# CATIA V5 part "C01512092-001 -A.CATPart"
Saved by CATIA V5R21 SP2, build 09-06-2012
Part number: C01512092-001
Revision: ---
Description: PROPRIETARY NOTICE (do not delete / modify)  ***************************************************************************************************  LA SOCIETE EN COMMANDITE  AIRBUS CANADA  ("AIRBUS CANADA")  PAR  L'INTERMEDIAIRE  DE  SES  DIVISIONS  ET/OU  FILIALES  CORPORATIVES,  FOURNIT  LES PRESENTES  INFORMATIONS  AU  GOUVERNEMENT  A  TITRE CONFIDENTIEL. CES  INFORMATIONS ONT UNE TENEUR CONFIDENTIELLE,  AVEC DROITS DE PROPRIETE,  ET NOUS LES CONSIDERONS  EXCLUS  DE   L'APPLICATION  DE  LA LOI SUR L'ACCES A L'INFORMATION  (CANADA),  LES  LOIS  SUR  L'ACCES  A  L'INFORMATION  EUROPEENNES,  LE FREEDOM OF INFORMATION ACT (ETATS-UNIS) ET D'AUTRES LOIS SEMBLABLES. ELLES  PEUVENT  AUSSI  CONSTITUER DES SECRETS INDUSTRIELS DE NOTRE SOCIETE OU DE TIERCES PARTIES. LA DIVULGATION  PUBLIQUE  DE CES  INFORMATIONS NUIRAIT A AIRBUS CANADA OU A DES TIERCES PARTIES.  CES INFORMATIONS PEUVENT EGALEMENT CONTENIR  DES DONNEES QUI SONT CONTROLEE PAR DES LOIS DE CONTROLE DES EXPORTATIONS DU CANADA, L’EUROPE OU LES  ETATS-  UNIS. TOUTE EXPORTATION OU REEXPORTATION DE DONNEES CONTROLEES SANS AUTORISATION EST STRICTEMENT INTERDITE.  TOUTE INTENTION DE LES DIVULGUER EN TOUT OU EN PARTIE DEVRA ETRE SIGNIFIEE A L'AVANCE ET PAR ECRIT AU VICE-  PRESIDENT, SERVICES JURIDIQUES ET CONFORMITE ET SECRETAIRE CORPORATIF D'AIRBUS CANADA.    AIRBUS CANADA LIMITED PARTNERSHIP  ("AIRBUS CANADA"),  BY ITS AFFILIATES AND/OR SUBSIDIARIES, PROVIDES THIS  INFORMATION TO THE GOVERNMENT IN CONFIDENCE. THIS IS PROPRIETARY CONFIDENTIAL INFORMATION WHICH WE CONSIDER  EXCLUDED  FROM  THE  APPLICATION OF THE ACCESS TO INFORMATION ACT (CANADA),  THE FREEDOM OF INFORMATION ACT  (U.S.A.),  THE ACCESS TO INFORMATION LAWS IN EUROPE, AND OTHER SIMILAR LEGISLATION. AND MAY ALSO CONSTITUTE  TRADE SECRETS OF OUR  COMPANY OR THIRD PARTIES.  PUBLIC  RELEASE  OF  THIS INFORMATION  WOULD BE HARMFUL TO  AIRBUS CANADA OR THIRD PARTIES.  THIS  INFORMATION  MAY  ALSO  CONTAIN DATA THAT IS CONTROLLED BY CANADIAN,  EUROPEAN, OR U.S.A. EXPORT CONTROL LAWS. ANY UNAUTHORIZED EXPORT OR RE-EXPORT OF ANY EXPORT CONTROLLED DATA  IS STRICTLY PROHIBITED  ANY INTENTION TO DISCLOSE SUCH INFORMATION,  OR  PART THEREOF,  MUST BE NOTIFIED IN  ADVANCE AND IN WRITING TO THE VICE PRESIDENT, LEGAL AND COMPLIANCE AND CORPORATE SECRETARY OF AIRBUS CANADA.        LES RENSEIGNEMENTS,  LES DONNEES  ET  DESSINS  TECHNIQUES  DIVULGUES  DANS  LES PRESENTES SONT LA PROPRIETE  EXCLUSIVE DE LA SOCIETE EN COMMANDITE AIRBUS CANADA ("AIRBUS CANADA") OU COMPORTENT DES DROITS DE PROPRIETE  APPARTENANT  A  AUTRUI ET NE PEUVENT ETRE DIVULGUES  A  QUICONQUE  NI  UTILISES PAR QUI QUE CE SOIT SANS LE  CONSENTEMENT  ECRIT  D’AIRBUS  CANADA.  LE DETENTEUR DES  PRESENTES  S'ENGAGE, DANS TOUTES CIRCONSTANCES, A  GARDER CONFIDENTIELS LES DONNEES ET DESSINS TECHNIQUES QU'ELLES CONTIENNENT.   CE QUI PRECEDE NE S'APPLIQUE  PAS  AUX PERSONNES  QUI  ONT DES DROITS DE PROPRIETE SUR CES RENSEIGNEMENTS,  DONNEES TECHNIQUES ET DESSINS  DANS LA MESURE OU CES DROITS EXISTENT.    THE INFORMATION,  TECHNICAL DATA  AND  DESIGNS DISCLOSED HEREIN ARE THE EXCLUSIVE PROPERTY OF AIRBUS CANADA  LIMITED PARTNERSHIP  ("AIRBUS CANADA")  OR  CONTAIN PROPRIETARY RIGHTS OF OTHERS  AND ARE NOT TO BE USED OR  DISCLOSED  TO  OTHERS WITHOUT THE WRITTEN CONSENT OF AIRBUS CANADA.  THE RECIPIENT OF THIS DOCUMENT, BY ITS  RETENTION  AND  USE  AGREES TO  HOLD  IN  CONFIDENCE  THE  TECHNICAL DATA AND DESIGNS CONTAINED HEREIN. THE  FOREGOING SHALL NOT APPLY TO PERSONS HAVING PROPRIETARY RIGHTS TO SUCH INFORMATION,  TECHNICAL DATA OR SUCH  DESIGNS TO THE EXTENT THAT SUCH RIGHTS EXIST.    Copyright 2020 Airbus Canada Limited Partnership. All Rights Reserved.  ***********************************
Property "Title": "LEVER, LIFT, FWD PASS DR"
Property "Dataset Type": "DETAIL"
Property "Supplier Name And CAGE Code": "AIRBUS CANADA LIMITED PARTNERSHIP L0J48"
Property "Major Supplier Code": "LP"
Property "3D Only": "N/A"
Property "Material Form": "BAR - FLAT"
Property "Finish Code": "S010"
Property "PCCN": "2"
Property "Organization": "DESIGN"
Property "Design Authority Program": "BD-500"
Property "Color Coded": "N/A"
Property "Thickness": 1.5
Property "Inside Diameter": 0
Property "Outside Diameter": 0
Property "Length": 0
Property "Width": 3.75
Property "Wall": 0
Property "Wire Gauge": "-"
Property "Alloy": "PH13-8MO"
Property "Final Condition": "H1000"
Property "Density": "N/A"
Property "Form": "N/A"
Property "Grade/Composition": "N/A"
Property "Material Class": "N/A"
Property "Mesh Cell Size": "N/A"
Property "Standard Spec Die": "N/A"
Property "Type": "N/A"
Property "Style": "N/A"
Property "MFG Process": "MACHINED"
Property "Material Specification Production": "AMS5629"
Property "Material Description Production": "CRES"
Property "Dimensions": "DIMENSIONS ARE IN INCHES"
Property "Roughness": "ALL MACHINED SURFACES 125 Ra MAX"
Property "Eng. Tolerances": "LINEAR .XX= +/-.03; .XXX= +/-.010; ANGULAR= +/-0.5 DEG"
Property "Tool Design Tolerances": "LINEAR .X= +/-.06; .XX= +/-.015; .XXX= +/-.005; .XXXX= +/-.001; ANGULAR= +/-0.5 DEG"
Property "Project": "BA"
Publications: "PartBody", "REFERENCE ORIENTATION", "REFERENCE PLANE", "REFERENCE AXIS", "Extract.1_Datum_A", "Extract.1_Datum_B", "Extract.1_Datum_C", "Extract.1_Datum_D"
Material "CRES-PH-13-8-MO-BAR": density 7750.37 kg/m3
Bounding box of the stored display mesh (mm): x -178.816 to 0, y -14.604 to 14.604, z -21.456 to 69.533
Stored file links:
  C:\Users\CQQZ006\Desktop\A220钢钛件\舱门\C01512092-001\C01512092-001 -A.CATPart
  I:\Standard\Materials\Textures\steel100.jpeg

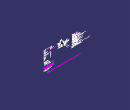
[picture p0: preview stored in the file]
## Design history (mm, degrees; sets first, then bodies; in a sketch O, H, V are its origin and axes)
Part_3D_Annotations1 "CATTPSSet"
AxisSystem1: origin (0, 0, 0), X (1, 0, 0), Y (0, 1, 0), Z (0, 0, 1)
Set1 "Pilot_Holes"
  Set2 "1/4"
    Set3 "Copied From C01512050-001"
      Line1 "Fix Orientation 1": stored without definition
      Point1 "Fix Point 1": stored without definition
      Line2 "Fix Orientation 2": stored without definition
      Point2 "Fix Point 2": stored without definition
Set4 "References"
  Line3 "REFERENCE ORIENTATION": type PtDir, RefPoint Point3, Direction yz-plane, Start -25.4, End 6.35
  Plane1 "REFERENCE PLANE": type Offset, RefPlane face of Shaft1 from Sketch1.L10, Offset 0, reversed
  Line4 "REFERENCE AXIS": type PtPt, FirstPoint Point4, SecondPoint Point5
Set5 "Geometrical Set for 3D Annotations"
  Set6 "No Show Geometry"
    Extract1 "Extract.1_Datum_A": ExtractElem face of Shaft1 from Sketch1.L11
    Extract2 "Extract.1_Datum_B": ExtractElem face of Shaft1 from Sketch1.L4
    Extract3 "Extract.1_Datum_C": ExtractElem face of Pocket1 from Sketch2.A3
    Extract4 "Extract.1_Datum_D": ExtractElem end face of Pocket2
  Set7 "Surfaces for 3D Annotations"
    Plane2: type Offset, RefPlane face of Shaft1 from Sketch1.L7, Offset 2.54, reversed
    Split1: ToCut {extract ExtractElem face of Shaft1 from Sketch1.L8}, Cutting Plane2
Set8 "Construction_Geometry"
  Point3: type Center, Curve edge [face of Chamfer2 | face of Shaft1 from Sketch1.L1]
  Point4: type Center, Curve edge [end face of Pocket2 | face of Shaft1 from Sketch1.L12]
  Point5: type Center, Curve edge [face of Shaft1 from Sketch1.L9 | face of Shaft1 from Sketch1.L14]
Body1 (main body)
  Sketch1 on zx-plane, origin (0, 0, 0), H (-1, 0, 0), V (0, 0, 1)
    line L1 (0, 9.525) -> (0, 76.2)
    line L2 (0, 76.2) -> (15.24, 76.2)
    line L3 (15.24, 76.2) -> (15.24, 19.064)
    arc A1 centre (20.828, 19.064) radius 5.588 from (15.24, 19.064) to (20.828, 13.476) ccw
    line L4 (20.828, 13.476) -> (41.91, 13.476)
    point P6 (41.91, 13.476)
    arc A2 centre (47.7279, 24.765) radius 12.7 from (41.91, 13.476) to (47.7279, 12.065) ccw
    line L5 (47.7279, 12.065) -> (105.4477, 12.065)
    arc A3 centre (105.4477, 24.765) radius 12.7 from (105.4477, 12.065) to (109.347, 12.6784) ccw
    line L6 (161.163, 9.5072) -> (167.386, 9.5072)
    line L7 (167.386, 9.5072) -> (167.386, 6.604)
    line L8 (167.64, 6.35) -> (178.816, 6.35)
    line L9 (178.816, 6.35) -> (178.816, 3.175)
    line L10 (160.909, 9.7612) -> (160.909, 12.6784)
    point P13 (160.909, 12.6784)
    line L11 (160.909, 12.6784) -> (109.347, 12.6784)
    point P14 (109.347, 12.6784)
    arc A4 centre (161.163, 9.7612) radius 0.254 from (160.909, 9.7612) to (161.163, 9.5072) ccw
    line L12 (0, 9.525) -> (154.559, 9.525)
    point P18 (154.559, 9.525)
    line L13 (154.559, 9.525) -> (158.2252, 3.175)
    line L14 (158.2252, 3.175) -> (178.816, 3.175)
    construction line L15 (116.4249, -12.6784) -> (142.4659, -12.6784)
    construction line L16 (161.544, -9.5072) -> (167.3073, -9.5072)
    construction line L17 (23.5752, -13.476) -> (37.3676, -13.476)
    construction line L18 (111.379, 13.7142) -> (111.379, 7.238)
    construction line L19 (39.878, 16.0174) -> (39.878, 10.4929)
    arc A5 centre (167.64, 6.604) radius 0.254 from (167.386, 6.604) to (167.64, 6.35) ccw
    distance H L2 = 76.2
    distance L5 H = 12.065
    radius A3 = 12.7
    radius A2 = 12.7
    length L2 = 15.24
    radius A1 = 5.588
    distance L9 L7 = 11.43
    distance L8 H = 6.35
    distance P6 V = 41.91
    distance L1 L10 = 160.909
    length L11 = 51.562
    distance L10 L7 = 6.477
    radius A4 = 0.254
    distance L12 H = 9.525
    distance P13 P18 H = 6.35
    distance L14 H = 3.175
    angle L13 L14 = 60
    distance L6 H = 9.5072 (reference)
    distance L12 L5 = 2.54 (reference)
    distance L15 L11 = 25.3568
    distance L6 L16 = 19.0144
    distance L17 L4 = 26.9519
    distance L18 P14 = 2.032
    distance L19 P6 = 2.032
    radius A5 = 0.254
    vertical: L1 V, L3 V, L7 V, L9 V, L10 V, L18 V, L19 V
    horizontal: L2 H, L5 H, L6 H, L8 H, L11 H, L12 H, L14 H, L15 H, L16 H, L17 H
    tangency: A1 L3, L4 A1, A3 L5, A2 L5, A4 L10, A4 L6, A5 L7, A5 L8
    coincidence: O L1
    symmetry: L15 L11 H, L16 L6 H, L17 L4 H
  Shaft1: profile Sketch1, axis Sketch1.H, angle 360
  Body2
    Sketch2 on yz-plane, origin (0, 0, 0), H (0, 1, 0), V (0, 0, -1)
      arc A1 centre (0, 0) radius 14.605 from (14.5789, -0.8731) to (-14.5789, -0.8731) ccw
      construction line L1 (0, 0) -> (0, -58.42)
      arc A2 centre (0, -58.42) radius 11.1125 from (-11.0926, -59.0843) to (11.0926, -59.0843) ccw
      line L2 (-14.5789, -0.8731) -> (-11.0926, -59.0843)
      line L3 (14.5789, -0.8731) -> (11.0926, -59.0843)
      circle A3 centre (0, -58.42) radius 5.5632
      projected circle E1 centre (0, 0) radius 76.2 from edge [face of Shaft1 from Sketch1.L1 | face of Shaft1 from Sketch1.L2]
      length L1 = 58.42
      radius A2 = 11.1125
      radius A1 = 14.605
      radius A3 = 5.5632
      tangency: L2 A2, L2 A1, L3 A2, L3 A1
      coincidence: L1 V
    Pocket1: profile Sketch2, direction (1, 0, 0), length 5.08, opposite side length 25.4
  Assemble1: tool Body2
  Body3
    Sketch3 on yz-plane, origin (0, 0, 0), H (0, 1, 0), V (0, 0, 1)
      line L1 (-25.4, 76.2) -> (25.4, 76.2)
      line L2 (25.4, 76.2) -> (25.4, -25.4)
      line L3 (25.4, -25.4) -> (-25.4, -25.4)
      line L4 (-25.4, -25.4) -> (-25.4, 76.2)
      circle A1 centre (0, 58.42) radius 11.1125
      point P5 (0, 58.42)
      point P6 (0, 47.3075)
      reference projected arc E1 centre (0, 58.42) radius 11.1125 from (11.046, 59.6339) to (-11.046, 59.6339) ccw from edge [face of Shaft1 from Sketch1.L1 | face of Pocket1 from Sketch2.A2]
      distance L1 H = 76.2
      distance V L2 = 25.4
      distance V L4 = 25.4 {= Sketch3.distance(V L2)}
      distance H L3 = 25.4 {= Sketch3.distance(V L2)}
      horizontal: L1 H, L3 H
      vertical: L2 V, L4 V
      coincidence: P5 V, A1 P6, P6 V, A1 E1
    Pocket2: profile Sketch3, direction (-1, 0, 0), length 2.54
    Fillet1: radius 1.524, on edge [face of Pocket2 from Sketch3.A1 | end face of Pocket2]
  Assemble2: tool Body3
  Body4
    Sketch4 on yz-plane, origin (0, 0, 0), H (0, 1, 0), V (0, 0, 1)
      arc A1 centre (0, 0) radius 19.8254 from (0.1236, 19.8251) to (-0.1236, 19.8251) ccw
      line L1 (-6.4654, 40.7501) -> (-7.2672, 27.3621)
      line L2 (6.4654, 40.7501) -> (7.2672, 27.3621)
      reference intersected line E1 (-11.1053, 58.8731) -> (-14.5949, 0.606) from face of Pocket1 from Sketch2.L2
      reference intersected line E2 (14.5949, 0.606) -> (11.1053, 58.8731) from face of Pocket1 from Sketch2.L3
      arc A2 centre (0, 40.3629) radius 6.477 from (6.4654, 40.7501) to (-6.4654, 40.7501) ccw
      arc A3 centre (0.1679, 26.9369) radius 7.112 from (0.1236, 19.8251) to (7.2672, 27.3621) ccw
      arc A4 centre (-0.1679, 26.9369) radius 7.112 from (-0.1236, 19.8251) to (-7.2672, 27.3621) cw
      construction circle A5 centre (-0.1679, 26.9369) radius 13.462
      reference projected point E3 (0, 13.476) from Sketch1.L4
      distance L1 E1 = 5.715 {= Sketch4.distance(L2 E2)}
      distance L2 E2 = 5.715
      radius A2 = 6.477
      radius A3 = 7.112
      radius A4 = 7.112
      radius A5 = 13.462
      tangency: A2 L2, A2 L1, A3 A1, A3 L2, A4 A1, A4 L1
      coincidence: A5 E3
    Pocket3: profile Sketch4, direction (-1, 0, 0), length 25.4, opposite side up to end face of Pocket2, offset -5.715
    Fillet2: radius 1.524, on edge [start face of Pocket3 | face of Pocket3 from Sketch4.L1]
  Assemble3: tool Body4
  Chamfer1: length 1.651, angle 60, on edge [face of Shaft1 from Sketch1.L11 | face of Shaft1 from Sketch1.L10]
  Sketch5 on xy-plane, origin (0, 0, 0), H (1, 0, 0), V (0, 1, 0)
    circle A1 centre (-175.006, 0) radius 1.4097
    point P1 (-175.006, 0)
    reference projected line E1 through (0, 0) direction (-1, 0) from axis of face of Shaft1 from Sketch1.L8
    reference intersected line E2 through (-178.816, 0) direction (0, -1) from face of Shaft1 from Sketch1.L9
    radius A1 = 1.4097
    distance P1 E2 = 3.81
    coincidence: P1 E1
  Pocket4: profile Sketch5, direction (0, 0, -1), through (limit type 6), opposite side through (limit type 6)
  Chamfer2: length 1.016, angle 45, on edge [face of Shaft1 from Sketch1.L8 | face of Shaft1 from Sketch1.L9]; edge [face of Pocket2 from Sketch3.A1 | face of Shaft1 from Sketch1.L1]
